# Generated by FakeRAM 2.0
VERSION 5.7 ;
BUSBITCHARS "[]" ;
PROPERTYDEFINITIONS
  MACRO width INTEGER ;
  MACRO depth INTEGER ;
  MACRO banks INTEGER ;
END PROPERTYDEFINITIONS
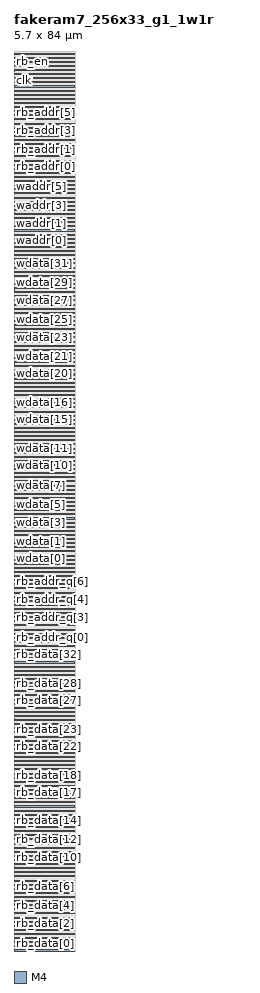
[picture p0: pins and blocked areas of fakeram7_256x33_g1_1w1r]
MACRO fakeram7_256x33_g1_1w1r
  PROPERTY width 33 ;
  PROPERTY depth 256 ;
  PROPERTY banks 1 ;
  FOREIGN fakeram7_256x33_g1_1w1r 0 0 ;
  SYMMETRY X Y R90 ;
  SIZE 5.7000 BY 84.0000 ;
  CLASS BLOCK ;
  PIN wdata[0]
    DIRECTION INPUT ;
    USE SIGNAL ;
    PORT
      LAYER M4 ;
      RECT 0.00000 36.62400 0.02400 36.64800 ;
    END
  END wdata[0]
  PIN wdata[1]
    DIRECTION INPUT ;
    USE SIGNAL ;
    PORT
      LAYER M4 ;
      RECT 0.00000 37.48800 0.02400 37.51200 ;
    END
  END wdata[1]
  PIN wdata[2]
    DIRECTION INPUT ;
    USE SIGNAL ;
    PORT
      LAYER M4 ;
      RECT 0.00000 38.35200 0.02400 38.37600 ;
    END
  END wdata[2]
  PIN wdata[3]
    DIRECTION INPUT ;
    USE SIGNAL ;
    PORT
      LAYER M4 ;
      RECT 0.00000 39.21600 0.02400 39.24000 ;
    END
  END wdata[3]
  PIN wdata[4]
    DIRECTION INPUT ;
    USE SIGNAL ;
    PORT
      LAYER M4 ;
      RECT 0.00000 40.08000 0.02400 40.10400 ;
    END
  END wdata[4]
  PIN wdata[5]
    DIRECTION INPUT ;
    USE SIGNAL ;
    PORT
      LAYER M4 ;
      RECT 0.00000 40.94400 0.02400 40.96800 ;
    END
  END wdata[5]
  PIN wdata[6]
    DIRECTION INPUT ;
    USE SIGNAL ;
    PORT
      LAYER M4 ;
      RECT 0.00000 41.80800 0.02400 41.83200 ;
    END
  END wdata[6]
  PIN wdata[7]
    DIRECTION INPUT ;
    USE SIGNAL ;
    PORT
      LAYER M4 ;
      RECT 0.00000 42.67200 0.02400 42.69600 ;
    END
  END wdata[7]
  PIN wdata[8]
    DIRECTION INPUT ;
    USE SIGNAL ;
    PORT
      LAYER M4 ;
      RECT 0.00000 43.53600 0.02400 43.56000 ;
    END
  END wdata[8]
  PIN wdata[9]
    DIRECTION INPUT ;
    USE SIGNAL ;
    PORT
      LAYER M4 ;
      RECT 0.00000 44.40000 0.02400 44.42400 ;
    END
  END wdata[9]
  PIN wdata[10]
    DIRECTION INPUT ;
    USE SIGNAL ;
    PORT
      LAYER M4 ;
      RECT 0.00000 45.26400 0.02400 45.28800 ;
    END
  END wdata[10]
  PIN wdata[11]
    DIRECTION INPUT ;
    USE SIGNAL ;
    PORT
      LAYER M4 ;
      RECT 0.00000 46.12800 0.02400 46.15200 ;
    END
  END wdata[11]
  PIN wdata[12]
    DIRECTION INPUT ;
    USE SIGNAL ;
    PORT
      LAYER M4 ;
      RECT 0.00000 46.99200 0.02400 47.01600 ;
    END
  END wdata[12]
  PIN wdata[13]
    DIRECTION INPUT ;
    USE SIGNAL ;
    PORT
      LAYER M4 ;
      RECT 0.00000 47.85600 0.02400 47.88000 ;
    END
  END wdata[13]
  PIN wdata[14]
    DIRECTION INPUT ;
    USE SIGNAL ;
    PORT
      LAYER M4 ;
      RECT 0.00000 48.72000 0.02400 48.74400 ;
    END
  END wdata[14]
  PIN wdata[15]
    DIRECTION INPUT ;
    USE SIGNAL ;
    PORT
      LAYER M4 ;
      RECT 0.00000 49.58400 0.02400 49.60800 ;
    END
  END wdata[15]
  PIN wdata[16]
    DIRECTION INPUT ;
    USE SIGNAL ;
    PORT
      LAYER M4 ;
      RECT 0.00000 50.44800 0.02400 50.47200 ;
    END
  END wdata[16]
  PIN wdata[17]
    DIRECTION INPUT ;
    USE SIGNAL ;
    PORT
      LAYER M4 ;
      RECT 0.00000 51.31200 0.02400 51.33600 ;
    END
  END wdata[17]
  PIN wdata[18]
    DIRECTION INPUT ;
    USE SIGNAL ;
    PORT
      LAYER M4 ;
      RECT 0.00000 52.17600 0.02400 52.20000 ;
    END
  END wdata[18]
  PIN wdata[19]
    DIRECTION INPUT ;
    USE SIGNAL ;
    PORT
      LAYER M4 ;
      RECT 0.00000 53.04000 0.02400 53.06400 ;
    END
  END wdata[19]
  PIN wdata[20]
    DIRECTION INPUT ;
    USE SIGNAL ;
    PORT
      LAYER M4 ;
      RECT 0.00000 53.90400 0.02400 53.92800 ;
    END
  END wdata[20]
  PIN wdata[21]
    DIRECTION INPUT ;
    USE SIGNAL ;
    PORT
      LAYER M4 ;
      RECT 0.00000 54.76800 0.02400 54.79200 ;
    END
  END wdata[21]
  PIN wdata[22]
    DIRECTION INPUT ;
    USE SIGNAL ;
    PORT
      LAYER M4 ;
      RECT 0.00000 55.63200 0.02400 55.65600 ;
    END
  END wdata[22]
  PIN wdata[23]
    DIRECTION INPUT ;
    USE SIGNAL ;
    PORT
      LAYER M4 ;
      RECT 0.00000 56.49600 0.02400 56.52000 ;
    END
  END wdata[23]
  PIN wdata[24]
    DIRECTION INPUT ;
    USE SIGNAL ;
    PORT
      LAYER M4 ;
      RECT 0.00000 57.36000 0.02400 57.38400 ;
    END
  END wdata[24]
  PIN wdata[25]
    DIRECTION INPUT ;
    USE SIGNAL ;
    PORT
      LAYER M4 ;
      RECT 0.00000 58.22400 0.02400 58.24800 ;
    END
  END wdata[25]
  PIN wdata[26]
    DIRECTION INPUT ;
    USE SIGNAL ;
    PORT
      LAYER M4 ;
      RECT 0.00000 59.08800 0.02400 59.11200 ;
    END
  END wdata[26]
  PIN wdata[27]
    DIRECTION INPUT ;
    USE SIGNAL ;
    PORT
      LAYER M4 ;
      RECT 0.00000 59.95200 0.02400 59.97600 ;
    END
  END wdata[27]
  PIN wdata[28]
    DIRECTION INPUT ;
    USE SIGNAL ;
    PORT
      LAYER M4 ;
      RECT 0.00000 60.81600 0.02400 60.84000 ;
    END
  END wdata[28]
  PIN wdata[29]
    DIRECTION INPUT ;
    USE SIGNAL ;
    PORT
      LAYER M4 ;
      RECT 0.00000 61.68000 0.02400 61.70400 ;
    END
  END wdata[29]
  PIN wdata[30]
    DIRECTION INPUT ;
    USE SIGNAL ;
    PORT
      LAYER M4 ;
      RECT 0.00000 62.54400 0.02400 62.56800 ;
    END
  END wdata[30]
  PIN wdata[31]
    DIRECTION INPUT ;
    USE SIGNAL ;
    PORT
      LAYER M4 ;
      RECT 0.00000 63.40800 0.02400 63.43200 ;
    END
  END wdata[31]
  PIN wdata[32]
    DIRECTION INPUT ;
    USE SIGNAL ;
    PORT
      LAYER M4 ;
      RECT 0.00000 64.27200 0.02400 64.29600 ;
    END
  END wdata[32]
  PIN waddr[0]
    DIRECTION INPUT ;
    USE SIGNAL ;
    PORT
      LAYER M4 ;
      RECT 0.00000 66.28800 0.02400 66.31200 ;
    END
  END waddr[0]
  PIN waddr[1]
    DIRECTION INPUT ;
    USE SIGNAL ;
    PORT
      LAYER M4 ;
      RECT 0.00000 67.15200 0.02400 67.17600 ;
    END
  END waddr[1]
  PIN waddr[2]
    DIRECTION INPUT ;
    USE SIGNAL ;
    PORT
      LAYER M4 ;
      RECT 0.00000 68.01600 0.02400 68.04000 ;
    END
  END waddr[2]
  PIN waddr[3]
    DIRECTION INPUT ;
    USE SIGNAL ;
    PORT
      LAYER M4 ;
      RECT 0.00000 68.88000 0.02400 68.90400 ;
    END
  END waddr[3]
  PIN waddr[4]
    DIRECTION INPUT ;
    USE SIGNAL ;
    PORT
      LAYER M4 ;
      RECT 0.00000 69.74400 0.02400 69.76800 ;
    END
  END waddr[4]
  PIN waddr[5]
    DIRECTION INPUT ;
    USE SIGNAL ;
    PORT
      LAYER M4 ;
      RECT 0.00000 70.60800 0.02400 70.63200 ;
    END
  END waddr[5]
  PIN waddr[6]
    DIRECTION INPUT ;
    USE SIGNAL ;
    PORT
      LAYER M4 ;
      RECT 0.00000 71.47200 0.02400 71.49600 ;
    END
  END waddr[6]
  PIN waddr[7]
    DIRECTION INPUT ;
    USE SIGNAL ;
    PORT
      LAYER M4 ;
      RECT 0.00000 72.33600 0.02400 72.36000 ;
    END
  END waddr[7]
  PIN rb_data[0]
    DIRECTION OUTPUT ;
    USE SIGNAL ;
    PORT
      LAYER M4 ;
      RECT 0.00000 0.04800 0.02400 0.07200 ;
    END
  END rb_data[0]
  PIN rb_data[1]
    DIRECTION OUTPUT ;
    USE SIGNAL ;
    PORT
      LAYER M4 ;
      RECT 0.00000 0.91200 0.02400 0.93600 ;
    END
  END rb_data[1]
  PIN rb_data[2]
    DIRECTION OUTPUT ;
    USE SIGNAL ;
    PORT
      LAYER M4 ;
      RECT 0.00000 1.77600 0.02400 1.80000 ;
    END
  END rb_data[2]
  PIN rb_data[3]
    DIRECTION OUTPUT ;
    USE SIGNAL ;
    PORT
      LAYER M4 ;
      RECT 0.00000 2.64000 0.02400 2.66400 ;
    END
  END rb_data[3]
  PIN rb_data[4]
    DIRECTION OUTPUT ;
    USE SIGNAL ;
    PORT
      LAYER M4 ;
      RECT 0.00000 3.50400 0.02400 3.52800 ;
    END
  END rb_data[4]
  PIN rb_data[5]
    DIRECTION OUTPUT ;
    USE SIGNAL ;
    PORT
      LAYER M4 ;
      RECT 0.00000 4.36800 0.02400 4.39200 ;
    END
  END rb_data[5]
  PIN rb_data[6]
    DIRECTION OUTPUT ;
    USE SIGNAL ;
    PORT
      LAYER M4 ;
      RECT 0.00000 5.23200 0.02400 5.25600 ;
    END
  END rb_data[6]
  PIN rb_data[7]
    DIRECTION OUTPUT ;
    USE SIGNAL ;
    PORT
      LAYER M4 ;
      RECT 0.00000 6.09600 0.02400 6.12000 ;
    END
  END rb_data[7]
  PIN rb_data[8]
    DIRECTION OUTPUT ;
    USE SIGNAL ;
    PORT
      LAYER M4 ;
      RECT 0.00000 6.96000 0.02400 6.98400 ;
    END
  END rb_data[8]
  PIN rb_data[9]
    DIRECTION OUTPUT ;
    USE SIGNAL ;
    PORT
      LAYER M4 ;
      RECT 0.00000 7.82400 0.02400 7.84800 ;
    END
  END rb_data[9]
  PIN rb_data[10]
    DIRECTION OUTPUT ;
    USE SIGNAL ;
    PORT
      LAYER M4 ;
      RECT 0.00000 8.68800 0.02400 8.71200 ;
    END
  END rb_data[10]
  PIN rb_data[11]
    DIRECTION OUTPUT ;
    USE SIGNAL ;
    PORT
      LAYER M4 ;
      RECT 0.00000 9.55200 0.02400 9.57600 ;
    END
  END rb_data[11]
  PIN rb_data[12]
    DIRECTION OUTPUT ;
    USE SIGNAL ;
    PORT
      LAYER M4 ;
      RECT 0.00000 10.41600 0.02400 10.44000 ;
    END
  END rb_data[12]
  PIN rb_data[13]
    DIRECTION OUTPUT ;
    USE SIGNAL ;
    PORT
      LAYER M4 ;
      RECT 0.00000 11.28000 0.02400 11.30400 ;
    END
  END rb_data[13]
  PIN rb_data[14]
    DIRECTION OUTPUT ;
    USE SIGNAL ;
    PORT
      LAYER M4 ;
      RECT 0.00000 12.14400 0.02400 12.16800 ;
    END
  END rb_data[14]
  PIN rb_data[15]
    DIRECTION OUTPUT ;
    USE SIGNAL ;
    PORT
      LAYER M4 ;
      RECT 0.00000 13.00800 0.02400 13.03200 ;
    END
  END rb_data[15]
  PIN rb_data[16]
    DIRECTION OUTPUT ;
    USE SIGNAL ;
    PORT
      LAYER M4 ;
      RECT 0.00000 13.87200 0.02400 13.89600 ;
    END
  END rb_data[16]
  PIN rb_data[17]
    DIRECTION OUTPUT ;
    USE SIGNAL ;
    PORT
      LAYER M4 ;
      RECT 0.00000 14.73600 0.02400 14.76000 ;
    END
  END rb_data[17]
  PIN rb_data[18]
    DIRECTION OUTPUT ;
    USE SIGNAL ;
    PORT
      LAYER M4 ;
      RECT 0.00000 15.60000 0.02400 15.62400 ;
    END
  END rb_data[18]
  PIN rb_data[19]
    DIRECTION OUTPUT ;
    USE SIGNAL ;
    PORT
      LAYER M4 ;
      RECT 0.00000 16.46400 0.02400 16.48800 ;
    END
  END rb_data[19]
  PIN rb_data[20]
    DIRECTION OUTPUT ;
    USE SIGNAL ;
    PORT
      LAYER M4 ;
      RECT 0.00000 17.32800 0.02400 17.35200 ;
    END
  END rb_data[20]
  PIN rb_data[21]
    DIRECTION OUTPUT ;
    USE SIGNAL ;
    PORT
      LAYER M4 ;
      RECT 0.00000 18.19200 0.02400 18.21600 ;
    END
  END rb_data[21]
  PIN rb_data[22]
    DIRECTION OUTPUT ;
    USE SIGNAL ;
    PORT
      LAYER M4 ;
      RECT 0.00000 19.05600 0.02400 19.08000 ;
    END
  END rb_data[22]
  PIN rb_data[23]
    DIRECTION OUTPUT ;
    USE SIGNAL ;
    PORT
      LAYER M4 ;
      RECT 0.00000 19.92000 0.02400 19.94400 ;
    END
  END rb_data[23]
  PIN rb_data[24]
    DIRECTION OUTPUT ;
    USE SIGNAL ;
    PORT
      LAYER M4 ;
      RECT 0.00000 20.78400 0.02400 20.80800 ;
    END
  END rb_data[24]
  PIN rb_data[25]
    DIRECTION OUTPUT ;
    USE SIGNAL ;
    PORT
      LAYER M4 ;
      RECT 0.00000 21.64800 0.02400 21.67200 ;
    END
  END rb_data[25]
  PIN rb_data[26]
    DIRECTION OUTPUT ;
    USE SIGNAL ;
    PORT
      LAYER M4 ;
      RECT 0.00000 22.51200 0.02400 22.53600 ;
    END
  END rb_data[26]
  PIN rb_data[27]
    DIRECTION OUTPUT ;
    USE SIGNAL ;
    PORT
      LAYER M4 ;
      RECT 0.00000 23.37600 0.02400 23.40000 ;
    END
  END rb_data[27]
  PIN rb_data[28]
    DIRECTION OUTPUT ;
    USE SIGNAL ;
    PORT
      LAYER M4 ;
      RECT 0.00000 24.24000 0.02400 24.26400 ;
    END
  END rb_data[28]
  PIN rb_data[29]
    DIRECTION OUTPUT ;
    USE SIGNAL ;
    PORT
      LAYER M4 ;
      RECT 0.00000 25.10400 0.02400 25.12800 ;
    END
  END rb_data[29]
  PIN rb_data[30]
    DIRECTION OUTPUT ;
    USE SIGNAL ;
    PORT
      LAYER M4 ;
      RECT 0.00000 25.96800 0.02400 25.99200 ;
    END
  END rb_data[30]
  PIN rb_data[31]
    DIRECTION OUTPUT ;
    USE SIGNAL ;
    PORT
      LAYER M4 ;
      RECT 0.00000 26.83200 0.02400 26.85600 ;
    END
  END rb_data[31]
  PIN rb_data[32]
    DIRECTION OUTPUT ;
    USE SIGNAL ;
    PORT
      LAYER M4 ;
      RECT 0.00000 27.69600 0.02400 27.72000 ;
    END
  END rb_data[32]
  PIN rb_addr[0]
    DIRECTION INPUT ;
    USE SIGNAL ;
    PORT
      LAYER M4 ;
      RECT 0.00000 73.20000 0.02400 73.22400 ;
    END
  END rb_addr[0]
  PIN rb_addr[1]
    DIRECTION INPUT ;
    USE SIGNAL ;
    PORT
      LAYER M4 ;
      RECT 0.00000 74.06400 0.02400 74.08800 ;
    END
  END rb_addr[1]
  PIN rb_addr[2]
    DIRECTION INPUT ;
    USE SIGNAL ;
    PORT
      LAYER M4 ;
      RECT 0.00000 74.92800 0.02400 74.95200 ;
    END
  END rb_addr[2]
  PIN rb_addr[3]
    DIRECTION INPUT ;
    USE SIGNAL ;
    PORT
      LAYER M4 ;
      RECT 0.00000 75.79200 0.02400 75.81600 ;
    END
  END rb_addr[3]
  PIN rb_addr[4]
    DIRECTION INPUT ;
    USE SIGNAL ;
    PORT
      LAYER M4 ;
      RECT 0.00000 76.65600 0.02400 76.68000 ;
    END
  END rb_addr[4]
  PIN rb_addr[5]
    DIRECTION INPUT ;
    USE SIGNAL ;
    PORT
      LAYER M4 ;
      RECT 0.00000 77.52000 0.02400 77.54400 ;
    END
  END rb_addr[5]
  PIN rb_addr[6]
    DIRECTION INPUT ;
    USE SIGNAL ;
    PORT
      LAYER M4 ;
      RECT 0.00000 78.38400 0.02400 78.40800 ;
    END
  END rb_addr[6]
  PIN rb_addr[7]
    DIRECTION INPUT ;
    USE SIGNAL ;
    PORT
      LAYER M4 ;
      RECT 0.00000 79.24800 0.02400 79.27200 ;
    END
  END rb_addr[7]
  PIN we
    DIRECTION INPUT ;
    USE SIGNAL ;
    PORT
      LAYER M4 ;
      RECT 0.00000 82.12800 0.02400 82.15200 ;
    END
  END we
  PIN clk
    DIRECTION INPUT ;
    USE SIGNAL ;
    PORT
      LAYER M4 ;
      RECT 0.00000 81.26400 0.02400 81.28800 ;
    END
  END clk
  PIN rb_en
    DIRECTION INPUT ;
    USE SIGNAL ;
    PORT
      LAYER M4 ;
      RECT 0.00000 82.99200 0.02400 83.01600 ;
    END
  END rb_en
  PIN rb_addr_q[0]
    DIRECTION OUTPUT ;
    USE SIGNAL ;
    PORT
      LAYER M4 ;
      RECT 0.00000 28.56000 0.02400 28.58400 ;
    END
  END rb_addr_q[0]
  PIN rb_addr_q[1]
    DIRECTION OUTPUT ;
    USE SIGNAL ;
    PORT
      LAYER M4 ;
      RECT 0.00000 29.42400 0.02400 29.44800 ;
    END
  END rb_addr_q[1]
  PIN rb_addr_q[2]
    DIRECTION OUTPUT ;
    USE SIGNAL ;
    PORT
      LAYER M4 ;
      RECT 0.00000 30.28800 0.02400 30.31200 ;
    END
  END rb_addr_q[2]
  PIN rb_addr_q[3]
    DIRECTION OUTPUT ;
    USE SIGNAL ;
    PORT
      LAYER M4 ;
      RECT 0.00000 31.15200 0.02400 31.17600 ;
    END
  END rb_addr_q[3]
  PIN rb_addr_q[4]
    DIRECTION OUTPUT ;
    USE SIGNAL ;
    PORT
      LAYER M4 ;
      RECT 0.00000 32.01600 0.02400 32.04000 ;
    END
  END rb_addr_q[4]
  PIN rb_addr_q[5]
    DIRECTION OUTPUT ;
    USE SIGNAL ;
    PORT
      LAYER M4 ;
      RECT 0.00000 32.88000 0.02400 32.90400 ;
    END
  END rb_addr_q[5]
  PIN rb_addr_q[6]
    DIRECTION OUTPUT ;
    USE SIGNAL ;
    PORT
      LAYER M4 ;
      RECT 0.00000 33.74400 0.02400 33.76800 ;
    END
  END rb_addr_q[6]
  PIN rb_addr_q[7]
    DIRECTION OUTPUT ;
    USE SIGNAL ;
    PORT
      LAYER M4 ;
      RECT 0.00000 34.60800 0.02400 34.63200 ;
    END
  END rb_addr_q[7]
  PIN VDD
    DIRECTION INOUT ;
    USE POWER ;
    PORT
      LAYER M4 ;
      RECT 0.04800 0.38400 5.65200 0.48000 ;
      RECT 0.04800 1.15200 5.65200 1.24800 ;
      RECT 0.04800 1.92000 5.65200 2.01600 ;
      RECT 0.04800 2.68800 5.65200 2.78400 ;
      RECT 0.04800 3.45600 5.65200 3.55200 ;
      RECT 0.04800 4.22400 5.65200 4.32000 ;
      RECT 0.04800 4.99200 5.65200 5.08800 ;
      RECT 0.04800 5.76000 5.65200 5.85600 ;
      RECT 0.04800 6.52800 5.65200 6.62400 ;
      RECT 0.04800 7.29600 5.65200 7.39200 ;
      RECT 0.04800 8.06400 5.65200 8.16000 ;
      RECT 0.04800 8.83200 5.65200 8.92800 ;
      RECT 0.04800 9.60000 5.65200 9.69600 ;
      RECT 0.04800 10.36800 5.65200 10.46400 ;
      RECT 0.04800 11.13600 5.65200 11.23200 ;
      RECT 0.04800 11.90400 5.65200 12.00000 ;
      RECT 0.04800 12.67200 5.65200 12.76800 ;
      RECT 0.04800 13.44000 5.65200 13.53600 ;
      RECT 0.04800 14.20800 5.65200 14.30400 ;
      RECT 0.04800 14.97600 5.65200 15.07200 ;
      RECT 0.04800 15.74400 5.65200 15.84000 ;
      RECT 0.04800 16.51200 5.65200 16.60800 ;
      RECT 0.04800 17.28000 5.65200 17.37600 ;
      RECT 0.04800 18.04800 5.65200 18.14400 ;
      RECT 0.04800 18.81600 5.65200 18.91200 ;
      RECT 0.04800 19.58400 5.65200 19.68000 ;
      RECT 0.04800 20.35200 5.65200 20.44800 ;
      RECT 0.04800 21.12000 5.65200 21.21600 ;
      RECT 0.04800 21.88800 5.65200 21.98400 ;
      RECT 0.04800 22.65600 5.65200 22.75200 ;
      RECT 0.04800 23.42400 5.65200 23.52000 ;
      RECT 0.04800 24.19200 5.65200 24.28800 ;
      RECT 0.04800 24.96000 5.65200 25.05600 ;
      RECT 0.04800 25.72800 5.65200 25.82400 ;
      RECT 0.04800 26.49600 5.65200 26.59200 ;
      RECT 0.04800 27.26400 5.65200 27.36000 ;
      RECT 0.04800 28.03200 5.65200 28.12800 ;
      RECT 0.04800 28.80000 5.65200 28.89600 ;
      RECT 0.04800 29.56800 5.65200 29.66400 ;
      RECT 0.04800 30.33600 5.65200 30.43200 ;
      RECT 0.04800 31.10400 5.65200 31.20000 ;
      RECT 0.04800 31.87200 5.65200 31.96800 ;
      RECT 0.04800 32.64000 5.65200 32.73600 ;
      RECT 0.04800 33.40800 5.65200 33.50400 ;
      RECT 0.04800 34.17600 5.65200 34.27200 ;
      RECT 0.04800 34.94400 5.65200 35.04000 ;
      RECT 0.04800 35.71200 5.65200 35.80800 ;
      RECT 0.04800 36.48000 5.65200 36.57600 ;
      RECT 0.04800 37.24800 5.65200 37.34400 ;
      RECT 0.04800 38.01600 5.65200 38.11200 ;
      RECT 0.04800 38.78400 5.65200 38.88000 ;
      RECT 0.04800 39.55200 5.65200 39.64800 ;
      RECT 0.04800 40.32000 5.65200 40.41600 ;
      RECT 0.04800 41.08800 5.65200 41.18400 ;
      RECT 0.04800 41.85600 5.65200 41.95200 ;
      RECT 0.04800 42.62400 5.65200 42.72000 ;
      RECT 0.04800 43.39200 5.65200 43.48800 ;
      RECT 0.04800 44.16000 5.65200 44.25600 ;
      RECT 0.04800 44.92800 5.65200 45.02400 ;
      RECT 0.04800 45.69600 5.65200 45.79200 ;
      RECT 0.04800 46.46400 5.65200 46.56000 ;
      RECT 0.04800 47.23200 5.65200 47.32800 ;
      RECT 0.04800 48.00000 5.65200 48.09600 ;
      RECT 0.04800 48.76800 5.65200 48.86400 ;
      RECT 0.04800 49.53600 5.65200 49.63200 ;
      RECT 0.04800 50.30400 5.65200 50.40000 ;
      RECT 0.04800 51.07200 5.65200 51.16800 ;
      RECT 0.04800 51.84000 5.65200 51.93600 ;
      RECT 0.04800 52.60800 5.65200 52.70400 ;
      RECT 0.04800 53.37600 5.65200 53.47200 ;
      RECT 0.04800 54.14400 5.65200 54.24000 ;
      RECT 0.04800 54.91200 5.65200 55.00800 ;
      RECT 0.04800 55.68000 5.65200 55.77600 ;
      RECT 0.04800 56.44800 5.65200 56.54400 ;
      RECT 0.04800 57.21600 5.65200 57.31200 ;
      RECT 0.04800 57.98400 5.65200 58.08000 ;
      RECT 0.04800 58.75200 5.65200 58.84800 ;
      RECT 0.04800 59.52000 5.65200 59.61600 ;
      RECT 0.04800 60.28800 5.65200 60.38400 ;
      RECT 0.04800 61.05600 5.65200 61.15200 ;
      RECT 0.04800 61.82400 5.65200 61.92000 ;
      RECT 0.04800 62.59200 5.65200 62.68800 ;
      RECT 0.04800 63.36000 5.65200 63.45600 ;
      RECT 0.04800 64.12800 5.65200 64.22400 ;
      RECT 0.04800 64.89600 5.65200 64.99200 ;
      RECT 0.04800 65.66400 5.65200 65.76000 ;
      RECT 0.04800 66.43200 5.65200 66.52800 ;
      RECT 0.04800 67.20000 5.65200 67.29600 ;
      RECT 0.04800 67.96800 5.65200 68.06400 ;
      RECT 0.04800 68.73600 5.65200 68.83200 ;
      RECT 0.04800 69.50400 5.65200 69.60000 ;
      RECT 0.04800 70.27200 5.65200 70.36800 ;
      RECT 0.04800 71.04000 5.65200 71.13600 ;
      RECT 0.04800 71.80800 5.65200 71.90400 ;
      RECT 0.04800 72.57600 5.65200 72.67200 ;
      RECT 0.04800 73.34400 5.65200 73.44000 ;
      RECT 0.04800 74.11200 5.65200 74.20800 ;
      RECT 0.04800 74.88000 5.65200 74.97600 ;
      RECT 0.04800 75.64800 5.65200 75.74400 ;
      RECT 0.04800 76.41600 5.65200 76.51200 ;
      RECT 0.04800 77.18400 5.65200 77.28000 ;
      RECT 0.04800 77.95200 5.65200 78.04800 ;
      RECT 0.04800 78.72000 5.65200 78.81600 ;
      RECT 0.04800 79.48800 5.65200 79.58400 ;
      RECT 0.04800 80.25600 5.65200 80.35200 ;
      RECT 0.04800 81.02400 5.65200 81.12000 ;
      RECT 0.04800 81.79200 5.65200 81.88800 ;
      RECT 0.04800 82.56000 5.65200 82.65600 ;
      RECT 0.04800 83.32800 5.65200 83.42400 ;
    END
  END VDD
  PIN VSS
    DIRECTION INOUT ;
    USE GROUND ;
    PORT
      LAYER M4 ;
      RECT 0.04800 0.00000 5.65200 0.09600 ;
      RECT 0.04800 0.76800 5.65200 0.86400 ;
      RECT 0.04800 1.53600 5.65200 1.63200 ;
      RECT 0.04800 2.30400 5.65200 2.40000 ;
      RECT 0.04800 3.07200 5.65200 3.16800 ;
      RECT 0.04800 3.84000 5.65200 3.93600 ;
      RECT 0.04800 4.60800 5.65200 4.70400 ;
      RECT 0.04800 5.37600 5.65200 5.47200 ;
      RECT 0.04800 6.14400 5.65200 6.24000 ;
      RECT 0.04800 6.91200 5.65200 7.00800 ;
      RECT 0.04800 7.68000 5.65200 7.77600 ;
      RECT 0.04800 8.44800 5.65200 8.54400 ;
      RECT 0.04800 9.21600 5.65200 9.31200 ;
      RECT 0.04800 9.98400 5.65200 10.08000 ;
      RECT 0.04800 10.75200 5.65200 10.84800 ;
      RECT 0.04800 11.52000 5.65200 11.61600 ;
      RECT 0.04800 12.28800 5.65200 12.38400 ;
      RECT 0.04800 13.05600 5.65200 13.15200 ;
      RECT 0.04800 13.82400 5.65200 13.92000 ;
      RECT 0.04800 14.59200 5.65200 14.68800 ;
      RECT 0.04800 15.36000 5.65200 15.45600 ;
      RECT 0.04800 16.12800 5.65200 16.22400 ;
      RECT 0.04800 16.89600 5.65200 16.99200 ;
      RECT 0.04800 17.66400 5.65200 17.76000 ;
      RECT 0.04800 18.43200 5.65200 18.52800 ;
      RECT 0.04800 19.20000 5.65200 19.29600 ;
      RECT 0.04800 19.96800 5.65200 20.06400 ;
      RECT 0.04800 20.73600 5.65200 20.83200 ;
      RECT 0.04800 21.50400 5.65200 21.60000 ;
      RECT 0.04800 22.27200 5.65200 22.36800 ;
      RECT 0.04800 23.04000 5.65200 23.13600 ;
      RECT 0.04800 23.80800 5.65200 23.90400 ;
      RECT 0.04800 24.57600 5.65200 24.67200 ;
      RECT 0.04800 25.34400 5.65200 25.44000 ;
      RECT 0.04800 26.11200 5.65200 26.20800 ;
      RECT 0.04800 26.88000 5.65200 26.97600 ;
      RECT 0.04800 27.64800 5.65200 27.74400 ;
      RECT 0.04800 28.41600 5.65200 28.51200 ;
      RECT 0.04800 29.18400 5.65200 29.28000 ;
      RECT 0.04800 29.95200 5.65200 30.04800 ;
      RECT 0.04800 30.72000 5.65200 30.81600 ;
      RECT 0.04800 31.48800 5.65200 31.58400 ;
      RECT 0.04800 32.25600 5.65200 32.35200 ;
      RECT 0.04800 33.02400 5.65200 33.12000 ;
      RECT 0.04800 33.79200 5.65200 33.88800 ;
      RECT 0.04800 34.56000 5.65200 34.65600 ;
      RECT 0.04800 35.32800 5.65200 35.42400 ;
      RECT 0.04800 36.09600 5.65200 36.19200 ;
      RECT 0.04800 36.86400 5.65200 36.96000 ;
      RECT 0.04800 37.63200 5.65200 37.72800 ;
      RECT 0.04800 38.40000 5.65200 38.49600 ;
      RECT 0.04800 39.16800 5.65200 39.26400 ;
      RECT 0.04800 39.93600 5.65200 40.03200 ;
      RECT 0.04800 40.70400 5.65200 40.80000 ;
      RECT 0.04800 41.47200 5.65200 41.56800 ;
      RECT 0.04800 42.24000 5.65200 42.33600 ;
      RECT 0.04800 43.00800 5.65200 43.10400 ;
      RECT 0.04800 43.77600 5.65200 43.87200 ;
      RECT 0.04800 44.54400 5.65200 44.64000 ;
      RECT 0.04800 45.31200 5.65200 45.40800 ;
      RECT 0.04800 46.08000 5.65200 46.17600 ;
      RECT 0.04800 46.84800 5.65200 46.94400 ;
      RECT 0.04800 47.61600 5.65200 47.71200 ;
      RECT 0.04800 48.38400 5.65200 48.48000 ;
      RECT 0.04800 49.15200 5.65200 49.24800 ;
      RECT 0.04800 49.92000 5.65200 50.01600 ;
      RECT 0.04800 50.68800 5.65200 50.78400 ;
      RECT 0.04800 51.45600 5.65200 51.55200 ;
      RECT 0.04800 52.22400 5.65200 52.32000 ;
      RECT 0.04800 52.99200 5.65200 53.08800 ;
      RECT 0.04800 53.76000 5.65200 53.85600 ;
      RECT 0.04800 54.52800 5.65200 54.62400 ;
      RECT 0.04800 55.29600 5.65200 55.39200 ;
      RECT 0.04800 56.06400 5.65200 56.16000 ;
      RECT 0.04800 56.83200 5.65200 56.92800 ;
      RECT 0.04800 57.60000 5.65200 57.69600 ;
      RECT 0.04800 58.36800 5.65200 58.46400 ;
      RECT 0.04800 59.13600 5.65200 59.23200 ;
      RECT 0.04800 59.90400 5.65200 60.00000 ;
      RECT 0.04800 60.67200 5.65200 60.76800 ;
      RECT 0.04800 61.44000 5.65200 61.53600 ;
      RECT 0.04800 62.20800 5.65200 62.30400 ;
      RECT 0.04800 62.97600 5.65200 63.07200 ;
      RECT 0.04800 63.74400 5.65200 63.84000 ;
      RECT 0.04800 64.51200 5.65200 64.60800 ;
      RECT 0.04800 65.28000 5.65200 65.37600 ;
      RECT 0.04800 66.04800 5.65200 66.14400 ;
      RECT 0.04800 66.81600 5.65200 66.91200 ;
      RECT 0.04800 67.58400 5.65200 67.68000 ;
      RECT 0.04800 68.35200 5.65200 68.44800 ;
      RECT 0.04800 69.12000 5.65200 69.21600 ;
      RECT 0.04800 69.88800 5.65200 69.98400 ;
      RECT 0.04800 70.65600 5.65200 70.75200 ;
      RECT 0.04800 71.42400 5.65200 71.52000 ;
      RECT 0.04800 72.19200 5.65200 72.28800 ;
      RECT 0.04800 72.96000 5.65200 73.05600 ;
      RECT 0.04800 73.72800 5.65200 73.82400 ;
      RECT 0.04800 74.49600 5.65200 74.59200 ;
      RECT 0.04800 75.26400 5.65200 75.36000 ;
      RECT 0.04800 76.03200 5.65200 76.12800 ;
      RECT 0.04800 76.80000 5.65200 76.89600 ;
      RECT 0.04800 77.56800 5.65200 77.66400 ;
      RECT 0.04800 78.33600 5.65200 78.43200 ;
      RECT 0.04800 79.10400 5.65200 79.20000 ;
      RECT 0.04800 79.87200 5.65200 79.96800 ;
      RECT 0.04800 80.64000 5.65200 80.73600 ;
      RECT 0.04800 81.40800 5.65200 81.50400 ;
      RECT 0.04800 82.17600 5.65200 82.27200 ;
      RECT 0.04800 82.94400 5.65200 83.04000 ;
      RECT 0.04800 83.71200 5.65200 83.80800 ;
    END
  END VSS
  OBS
    LAYER M1 ;
    RECT 0 0 5.70000 84.00000 ;
    LAYER M2 ;
    RECT 0 0 5.70000 84.00000 ;
    LAYER M3 ;
    RECT 0 0 5.70000 84.00000 ;
    LAYER M4 ;
    RECT 0 0 5.70000 84.00000 ;
  END
END fakeram7_256x33_g1_1w1r

END LIBRARY
